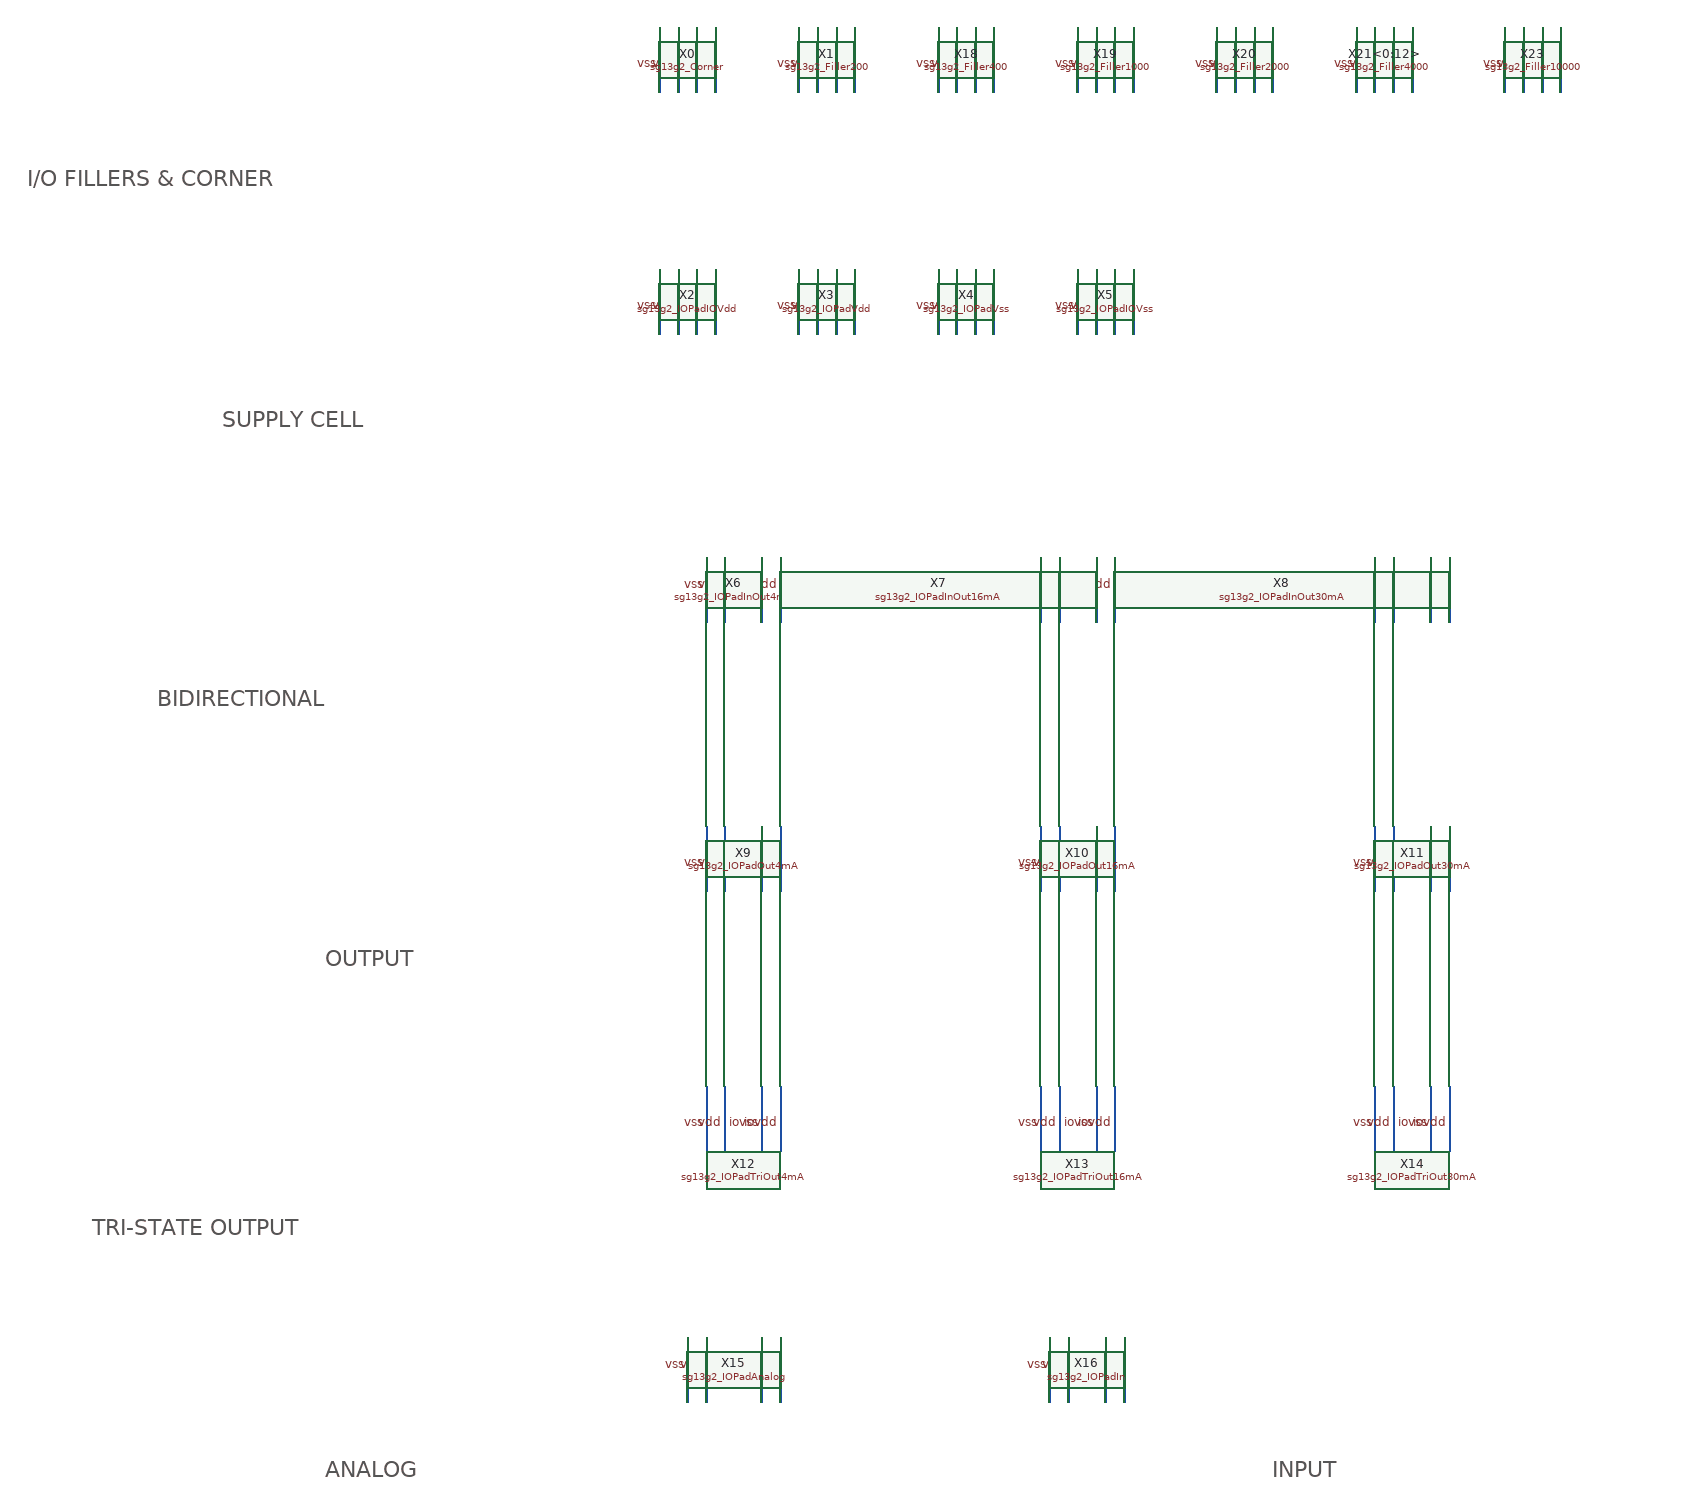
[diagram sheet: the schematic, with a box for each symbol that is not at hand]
v {xschem version=3.4.8RC file_version=1.3}
G {}
K {}
V {}
S {}
F {}
E {}
T {I/O FILLERS & CORNER} -560 -390 0 0 1 1 {}
T {SUPPLY CELL} -350 -130 0 0 1 1 {}
T {BIDIRECTIONAL} -420 170 0 0 1 1 {}
T {OUTPUT} -240 450 0 0 1 1 {}
T {TRI-STATE OUTPUT} -490 740 0 0 1 1 {}
T {ANALOG} -240 1000 0 0 1 1 {}
T {INPUT} 780 1000 0 0 1 1 {}
N 120 -280 120 -210 {lab=vss}
N 140 -280 140 -210 {lab=vdd}
N 160 -280 160 -210 {lab=iovss}
N 180 -280 180 -210 {lab=iovdd}
N 590 -280 590 -210 {lab=vdd}
N 610 -280 610 -210 {lab=iovss}
N 630 -280 630 -210 {lab=iovdd}
N 570 -280 570 -210 {lab=vss}
N 270 -280 270 -210 {lab=vss}
N 330 -280 330 -210 {lab=iovdd}
N 310 -280 310 -210 {lab=iovss}
N 290 -280 290 -210 {lab=vdd}
N 440 -280 440 -210 {lab=vdd}
N 460 -280 460 -210 {lab=iovss}
N 480 -280 480 -210 {lab=iovdd}
N 420 -280 420 -210 {lab=vss}
N 760 -540 760 -470 {lab=iovss}
N 910 -540 910 -470 {lab=iovss}
N 720 -540 720 -470 {lab=vss}
N 740 -540 740 -470 {lab=vdd}
N 170 30 170 100 {lab=vss}
N 250 30 250 100 {lab=iovdd}
N 230 30 230 100 {lab=iovss}
N 190 30 190 100 {lab=vdd}
N 890 30 890 100 {lab=vss}
N 970 30 970 100 {lab=iovdd}
N 950 30 950 100 {lab=iovss}
N 910 30 910 100 {lab=vdd}
N 190 320 190 390 {lab=vdd}
N 230 320 230 390 {lab=iovss}
N 250 320 250 390 {lab=iovdd}
N 170 320 170 390 {lab=vss}
N 890 320 890 390 {lab=vss}
N 970 320 970 390 {lab=iovdd}
N 950 320 950 390 {lab=iovss}
N 910 320 910 390 {lab=vdd}
N 540 870 540 940 {lab=vss}
N 620 870 620 940 {lab=iovdd}
N 600 870 600 940 {lab=iovss}
N 560 870 560 940 {lab=vdd}
N 530 30 530 100 {lab=vss}
N 550 30 550 100 {lab=vdd}
N 590 30 590 100 {lab=iovss}
N 610 30 610 100 {lab=iovdd}
N 530 320 530 390 {lab=vss}
N 550 320 550 390 {lab=vdd}
N 590 320 590 390 {lab=iovss}
N 610 320 610 390 {lab=iovdd}
N 250 600 250 670 {lab=iovdd}
N 230 600 230 670 {lab=iovss}
N 190 600 190 670 {lab=vdd}
N 170 600 170 670 {lab=vss}
N 530 600 530 670 {lab=vss}
N 550 600 550 670 {lab=vdd}
N 590 600 590 670 {lab=iovss}
N 610 600 610 670 {lab=iovdd}
N 970 600 970 670 {lab=iovdd}
N 950 600 950 670 {lab=iovss}
N 910 600 910 670 {lab=vdd}
N 890 600 890 670 {lab=vss}
N 120 -540 120 -470 {lab=vss}
N 140 -540 140 -470 {lab=vdd}
N 160 -540 160 -470 {lab=iovss}
N 180 -540 180 -470 {lab=iovdd}
N 870 -540 870 -470 {lab=vss}
N 890 -540 890 -470 {lab=vdd}
N 930 -540 930 -470 {lab=iovdd}
N 1030 -540 1030 -470 {lab=vss}
N 780 -540 780 -470 {lab=iovdd}
N 630 -540 630 -470 {lab=iovdd}
N 610 -540 610 -470 {lab=iovss}
N 590 -540 590 -470 {lab=vdd}
N 270 -540 270 -470 {lab=vss}
N 290 -540 290 -470 {lab=vdd}
N 310 -540 310 -470 {lab=iovss}
N 330 -540 330 -470 {lab=iovdd}
N 420 -540 420 -470 {lab=vss}
N 440 -540 440 -470 {lab=vdd}
N 460 -540 460 -470 {lab=iovss}
N 480 -540 480 -470 {lab=iovdd}
N 570 -540 570 -470 {lab=vss}
N 150 870 150 940 {lab=vss}
N 170 870 170 940 {lab=vdd}
N 230 870 230 940 {lab=iovss}
N 250 870 250 940 {lab=iovdd}
N 1050 -540 1050 -470 {lab=vdd}
N 1070 -540 1070 -470 {lab=iovss}
N 1090 -540 1090 -470 {lab=iovdd}
C {lab_wire.sym} 120 -240 0 0 {name=l1 sig_type=std_logic lab=vss}
C {lab_wire.sym} 140 -240 0 0 {name=l2 sig_type=std_logic lab=vdd}
C {lab_wire.sym} 160 -240 0 0 {name=l3 sig_type=std_logic lab=iovss}
C {lab_wire.sym} 180 -240 0 0 {name=l4 sig_type=std_logic lab=iovdd}
C {lab_wire.sym} 590 -240 0 0 {name=l5 sig_type=std_logic lab=vdd}
C {lab_wire.sym} 610 -240 0 0 {name=l6 sig_type=std_logic lab=iovss}
C {lab_wire.sym} 630 -240 0 0 {name=l7 sig_type=std_logic lab=iovdd}
C {lab_wire.sym} 570 -240 0 0 {name=l8 sig_type=std_logic lab=vss}
C {lab_wire.sym} 270 -240 0 0 {name=l9 sig_type=std_logic lab=vss}
C {lab_wire.sym} 330 -240 0 0 {name=l10 sig_type=std_logic lab=iovdd}
C {lab_wire.sym} 310 -240 0 0 {name=l11 sig_type=std_logic lab=iovss}
C {lab_wire.sym} 290 -240 0 0 {name=l12 sig_type=std_logic lab=vdd}
C {lab_wire.sym} 440 -240 0 0 {name=l13 sig_type=std_logic lab=vdd}
C {lab_wire.sym} 460 -240 0 0 {name=l14 sig_type=std_logic lab=iovss}
C {lab_wire.sym} 480 -240 0 0 {name=l15 sig_type=std_logic lab=iovdd}
C {lab_wire.sym} 420 -240 0 0 {name=l16 sig_type=std_logic lab=vss}
C {lab_wire.sym} 760 -500 0 0 {name=l17 sig_type=std_logic lab=iovss}
C {lab_wire.sym} 910 -500 0 0 {name=l18 sig_type=std_logic lab=iovss}
C {lab_wire.sym} 720 -500 0 0 {name=l19 sig_type=std_logic lab=vss}
C {lab_wire.sym} 740 -500 0 0 {name=l20 sig_type=std_logic lab=vdd}
C {lab_wire.sym} 170 60 0 0 {name=l21 sig_type=std_logic lab=vss}
C {lab_wire.sym} 250 60 0 0 {name=l22 sig_type=std_logic lab=iovdd}
C {lab_wire.sym} 230 60 0 0 {name=l23 sig_type=std_logic lab=iovss}
C {lab_wire.sym} 190 60 0 0 {name=l24 sig_type=std_logic lab=vdd}
C {lab_wire.sym} 890 60 0 0 {name=l25 sig_type=std_logic lab=vss}
C {lab_wire.sym} 970 60 0 0 {name=l26 sig_type=std_logic lab=iovdd}
C {lab_wire.sym} 950 60 0 0 {name=l27 sig_type=std_logic lab=iovss}
C {lab_wire.sym} 910 60 0 0 {name=l28 sig_type=std_logic lab=vdd}
C {lab_wire.sym} 190 360 0 0 {name=l29 sig_type=std_logic lab=vdd}
C {lab_wire.sym} 230 360 0 0 {name=l30 sig_type=std_logic lab=iovss}
C {lab_wire.sym} 250 360 0 0 {name=l31 sig_type=std_logic lab=iovdd}
C {lab_wire.sym} 170 360 0 0 {name=l32 sig_type=std_logic lab=vss}
C {lab_wire.sym} 890 360 0 0 {name=l33 sig_type=std_logic lab=vss}
C {lab_wire.sym} 970 360 0 0 {name=l34 sig_type=std_logic lab=iovdd}
C {lab_wire.sym} 950 360 0 0 {name=l35 sig_type=std_logic lab=iovss}
C {lab_wire.sym} 910 360 0 0 {name=l36 sig_type=std_logic lab=vdd}
C {lab_wire.sym} 540 900 0 0 {name=l37 sig_type=std_logic lab=vss}
C {lab_wire.sym} 620 900 0 0 {name=l38 sig_type=std_logic lab=iovdd}
C {lab_wire.sym} 600 900 0 0 {name=l39 sig_type=std_logic lab=iovss}
C {lab_wire.sym} 560 900 0 0 {name=l40 sig_type=std_logic lab=vdd}
C {lab_wire.sym} 530 60 0 0 {name=l41 sig_type=std_logic lab=vss}
C {lab_wire.sym} 550 60 0 0 {name=l42 sig_type=std_logic lab=vdd}
C {lab_wire.sym} 590 60 0 0 {name=l43 sig_type=std_logic lab=iovss}
C {lab_wire.sym} 610 60 0 0 {name=l44 sig_type=std_logic lab=iovdd}
C {lab_wire.sym} 530 360 0 0 {name=l45 sig_type=std_logic lab=vss}
C {lab_wire.sym} 550 360 0 0 {name=l46 sig_type=std_logic lab=vdd}
C {lab_wire.sym} 590 360 0 0 {name=l47 sig_type=std_logic lab=iovss}
C {lab_wire.sym} 610 360 0 0 {name=l48 sig_type=std_logic lab=iovdd}
C {lab_wire.sym} 250 640 0 0 {name=l49 sig_type=std_logic lab=iovdd}
C {lab_wire.sym} 230 640 0 0 {name=l50 sig_type=std_logic lab=iovss}
C {lab_wire.sym} 190 640 0 0 {name=l51 sig_type=std_logic lab=vdd}
C {lab_wire.sym} 170 640 0 0 {name=l52 sig_type=std_logic lab=vss}
C {lab_wire.sym} 530 640 0 0 {name=l53 sig_type=std_logic lab=vss}
C {lab_wire.sym} 550 640 0 0 {name=l54 sig_type=std_logic lab=vdd}
C {lab_wire.sym} 590 640 0 0 {name=l55 sig_type=std_logic lab=iovss}
C {lab_wire.sym} 610 640 0 0 {name=l56 sig_type=std_logic lab=iovdd}
C {lab_wire.sym} 970 640 0 0 {name=l57 sig_type=std_logic lab=iovdd}
C {lab_wire.sym} 950 640 0 0 {name=l58 sig_type=std_logic lab=iovss}
C {lab_wire.sym} 910 640 0 0 {name=l59 sig_type=std_logic lab=vdd}
C {lab_wire.sym} 890 640 0 0 {name=l60 sig_type=std_logic lab=vss}
C {lab_wire.sym} 120 -500 0 0 {name=l61 sig_type=std_logic lab=vss}
C {lab_wire.sym} 140 -500 0 0 {name=l62 sig_type=std_logic lab=vdd}
C {lab_wire.sym} 160 -500 0 0 {name=l63 sig_type=std_logic lab=iovss}
C {lab_wire.sym} 180 -500 0 0 {name=l64 sig_type=std_logic lab=iovdd}
C {lab_wire.sym} 870 -500 0 0 {name=l65 sig_type=std_logic lab=vss}
C {lab_wire.sym} 890 -500 0 0 {name=l66 sig_type=std_logic lab=vdd}
C {lab_wire.sym} 930 -500 0 0 {name=l67 sig_type=std_logic lab=iovdd}
C {lab_wire.sym} 1030 -500 0 0 {name=l68 sig_type=std_logic lab=vss}
C {lab_wire.sym} 780 -500 0 0 {name=l69 sig_type=std_logic lab=iovdd}
C {lab_wire.sym} 630 -500 0 0 {name=l70 sig_type=std_logic lab=iovdd}
C {lab_wire.sym} 610 -500 0 0 {name=l71 sig_type=std_logic lab=iovss}
C {lab_wire.sym} 590 -500 0 0 {name=l72 sig_type=std_logic lab=vdd}
C {lab_wire.sym} 270 -500 0 0 {name=l73 sig_type=std_logic lab=vss}
C {lab_wire.sym} 290 -500 0 0 {name=l74 sig_type=std_logic lab=vdd}
C {lab_wire.sym} 310 -500 0 0 {name=l75 sig_type=std_logic lab=iovss}
C {lab_wire.sym} 330 -500 0 0 {name=l76 sig_type=std_logic lab=iovdd}
C {lab_wire.sym} 420 -500 0 0 {name=l77 sig_type=std_logic lab=vss}
C {lab_wire.sym} 440 -500 0 0 {name=l78 sig_type=std_logic lab=vdd}
C {lab_wire.sym} 460 -500 0 0 {name=l79 sig_type=std_logic lab=iovss}
C {lab_wire.sym} 480 -500 0 0 {name=l80 sig_type=std_logic lab=iovdd}
C {lab_wire.sym} 570 -500 0 0 {name=l81 sig_type=std_logic lab=vss}
C {lab_wire.sym} 150 900 0 0 {name=l82 sig_type=std_logic lab=vss}
C {lab_wire.sym} 170 900 0 0 {name=l83 sig_type=std_logic lab=vdd}
C {lab_wire.sym} 230 900 0 0 {name=l84 sig_type=std_logic lab=iovss}
C {lab_wire.sym} 250 900 0 0 {name=l85 sig_type=std_logic lab=iovdd}
C {lab_wire.sym} 1050 -500 0 0 {name=l86 sig_type=std_logic lab=vdd}
C {lab_wire.sym} 1070 -500 0 0 {name=l87 sig_type=std_logic lab=iovss}
C {lab_wire.sym} 1090 -500 0 0 {name=l88 sig_type=std_logic lab=iovdd}
C {sg13g2_Corner.sym} 120 -470 0 0 {name=X0}
C {sg13g2_Filler200.sym} 270 -470 0 0 {name=X1}
C {sg13g2_IOPadOut16mA.sym} 450 480 0 0 {name=X10}
C {sg13g2_IOPadOut30mA.sym} 810 480 0 0 {name=X11}
C {sg13g2_IOPadTriOut4mA.sym} 90 760 0 0 {name=X12}
C {sg13g2_IOPadTriOut16mA.sym} 450 760 0 0 {name=X13}
C {sg13g2_IOPadTriOut30mA.sym} 810 760 0 0 {name=X14}
C {sg13g2_IOPadAnalog.sym} 150 940 0 0 {name=X15}
C {sg13g2_IOPadIn.sym} 540 940 0 0 {name=X16}
C {sg13g2_Filler400.sym} 420 -470 0 0 {name=X18}
C {sg13g2_Filler1000.sym} 570 -470 0 0 {name=X19}
C {sg13g2_IOPadIOVdd.sym} 120 -210 0 0 {name=X2}
C {sg13g2_Filler2000.sym} 720 -470 0 0 {name=X20}
C {sg13g2_Filler4000.sym} 870 -470 0 0 {name=X21<0:12>}
C {sg13g2_Filler10000.sym} 1030 -470 0 0 {name=X23}
C {sg13g2_IOPadVdd.sym} 270 -210 0 0 {name=X3}
C {sg13g2_IOPadVss.sym} 420 -210 0 0 {name=X4}
C {sg13g2_IOPadIOVss.sym} 570 -210 0 0 {name=X5}
C {sg13g2_IOPadInOut4mA.sym} 60 190 0 0 {name=X6}
C {sg13g2_IOPadInOut16mA.sym} 420 190 0 0 {name=X7}
C {sg13g2_IOPadInOut30mA.sym} 780 190 0 0 {name=X8}
C {sg13g2_IOPadOut4mA.sym} 90 480 0 0 {name=X9}
C {devices/title-2.sym} -1140 1420 0 0 {name=l1 author="IHP PDK AUTHORS"}
